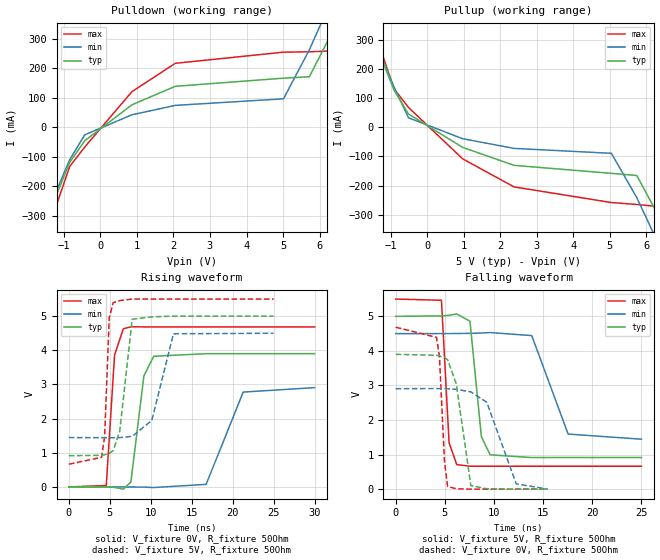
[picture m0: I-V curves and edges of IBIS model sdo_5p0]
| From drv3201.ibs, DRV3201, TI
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|   sdo_5p0 Model
[Model]   sdo_5p0
Model_type   Output
Polarity   Non-Inverting
Vmeas = 2.5
Vref = 0
Cref = 2pF
Rref = 300
|   typ   min   max
|   (nom PVT)   (fast PVT)   (slow PVT)
 C_comp   4.156e-12   3.993e-12   4.711e-12
| Where nom  PVT is Nominal Process, 5V, 27C
|   Fast PVT is Strong Process,  5.5V, -40C
|   Slow PVT is Weak Process,   4.5V, 150C
[Voltage Range]   5   4.5   5.5
|Junction Temperature
[Temperature Range]   27   150   -40
[Pullup Reference]   5   4.5   5.5
[Pulldown Reference]   0   0   0
[Power Clamp Reference]   5   4.5   5.5
[GND Clamp Reference]   0   0   0
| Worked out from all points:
|   slope of the pulldown table from 0 to 0.75 V, typ, clamps not added: 11.1 ohm
|   slope of the pullup table from 0 to 0.75 V, typ, clamps not added: 13.6 ohm
|   falling waveform, V_fixture 5V, R_fixture 50Ohm: 20-80 % time 741ps typ, 1.58ns min, 373ps max; typ from 5 V to 0.914 V
|   rising waveform, V_fixture 0V, R_fixture 50Ohm: 20-80 % time 1.01ns typ, 1.91ns min, 614ps max; typ from 0 V to 3.9 V
|   rising waveform, V_fixture 5V, R_fixture 50Ohm: 20-80 % time 733ps typ, 1.45ns min, 437ps max; typ from 0.914 V to 5 V
|   falling waveform, V_fixture 0V, R_fixture 50Ohm: 20-80 % time 983ps typ, 1.91ns min, 469ps max; typ from 3.9 V to 0 V
[Pulldown]
|   Voltage   I(typ)   I(min)   I(max)
-5V       -1.564A    -1.414A    -1.724A
-2.844V   -801.8mA   -722.4mA   -898.6mA
-1.375V   -282.9mA   -267.1mA   -326.5mA
-841.5mV  -119.7mA   -110.7mA   -134mA
-427.5mV  -46.2mA    -26.11mA   -67.41mA
863.5mV   75.69mA    41.89mA    120.2mA
2.051V    138.4mA    73.7mA     216.3mA
5.013V    166mA      96.02mA    254.1mA
5.72V     170.9mA    262.1mA    255.3mA
6.303V    311.4mA    424.2mA    258.4mA
6.891V    480.3mA    590.7mA    403.2mA
10V       1.469A     1.521A     1.429A
[Pullup]
|   Voltage   I(typ)   I(min)   I(max)
-5V       1.553A     1.452A     1.681A
-2.795V   773.3mA    730mA      842.4mA
-1.375V   273.1mA    276.8mA    302.4mA
-907.5mV  126.7mA    137.1mA    130.7mA
-513mV    45.04mA    32.06mA    67.37mA
968mV     -69.24mA   -39.56mA   -108.5mA
2.376V    -130.8mA   -72.78mA   -204.6mA
5.04V     -158.2mA   -89.55mA   -258.2mA
5.735V    -165.5mA   -241.2mA   -264.8mA
6.303V    -297.3mA   -392.6mA   -271.6mA
6.835V    -448.1mA   -537.1mA   -399.7mA
10V       -1.469A    -1.482A    -1.471A
[Ramp]
R_load = 50
|   typ   min   max
dV/dt_r   2.34058/1.00699e-09   1.74409/1.90147e-09   2.81133/6.09891e-10
dV/dt_f   2.45167/7.40092e-10   1.83304/1.56497e-09   2.90159/3.70435e-10
[Falling Waveform]
V_fixture = 5V
V_fixture_min = 4.5V
V_fixture_max = 5.5V
R_fixture = 50Ohm
|   Time   V(typ)   V(min)   V(max)
0s        5V         4.5V       5.5V
4.655ns   5.013V     4.501V     5.465V
5.432ns   5.032V     4.502V     1.339V
6.212ns   5.068V     4.503V     710.6mV
7.556ns   4.858V     4.508V     662.5mV
8.714ns   1.522V     4.517V     664mV
9.608ns   993.3mV    4.531V     664mV
13.84ns   914mV      4.443V     664mV
17.54ns   913.9mV    1.594V     664mV
25ns      913.9mV    1.445V     664mV
[Rising Waveform]
V_fixture = 0V
V_fixture_min = 0V
V_fixture_max = 0V
R_fixture = 50Ohm
|   Time   V(typ)   V(min)   V(max)
0s        2.412nV    151.2nV    5.105nV
4.571ns   -4.675mV   40.19uV    39.77mV
5.585ns   -15.52mV   -86.88uV   3.865V
6.653ns   -66.66mV   -764uV     4.631V
7.577ns   143.2mV    -2.086mV   4.688V
9.161ns   3.246V     -6.661mV   4.686V
10.36ns   3.826V     -18.85mV   4.685V
16.76ns   3.901V     74.03mV    4.686V
21.29ns   3.901V     2.777V     4.686V
30ns      3.901V     2.907V     4.686V
[Rising Waveform]
V_fixture = 5V
V_fixture_min = 4.5V
V_fixture_max = 5.5V
R_fixture = 50Ohm
|   Time   V(typ)   V(min)   V(max)
0s        913.9mV    1.445V     664mV
3.995ns   924.3mV    1.441V     866.5mV
4.37ns    939.5mV    1.44V      1.46V
4.934ns   983mV      1.44V      4.95V
5.417ns   1.063V     1.44V      5.397V
6.218ns   1.641V     1.443V     5.457V
7.736ns   4.911V     1.481V     5.501V
10.13ns   4.981V     1.945V     5.5V
12.77ns   5.001V     4.484V     5.5V
25ns      5V         4.5V       5.5V
[Falling Waveform]
V_fixture = 0V
V_fixture_min = 0V
V_fixture_max = 0V
R_fixture = 50Ohm
|   Time   V(typ)   V(min)   V(max)
0s        3.901V     2.907V     4.686V
4.145ns   3.873V     2.911V     4.392V
4.445ns   3.856V     2.91V      3.861V
4.967ns   3.804V     2.908V     794.1mV
5.282ns   3.746V     2.905V     79.44mV
6.167ns   3.042V     2.889V     9.179mV
7.646ns   101.9mV    2.814V     -484.6uV
9.266ns   12.77mV    2.513V     15.14uV
12.26ns   -58.73uV   152.9mV    -438.6nV
15.46ns   -58.51nV   1.817mV    -82.12nV
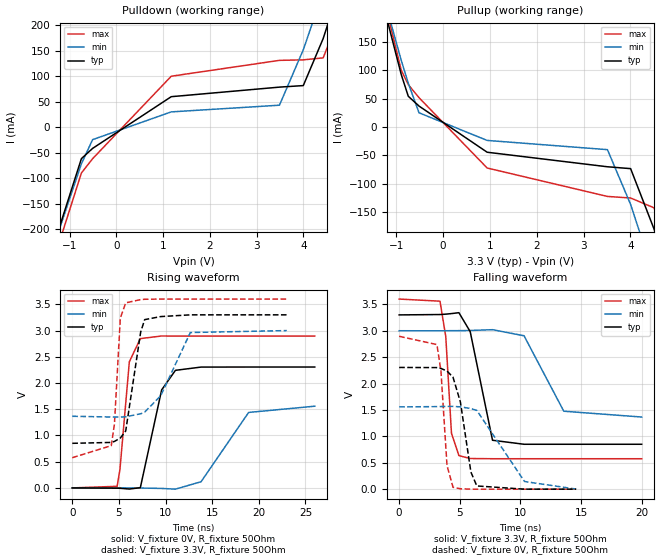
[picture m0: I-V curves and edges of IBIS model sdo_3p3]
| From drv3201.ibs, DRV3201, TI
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|   sdo_3p3 Model
[Model]   sdo_3p3
Model_type   Output
Polarity   Non-Inverting
Vmeas = 1.65
Vref = 0
Cref = 2pF
Rref = 300
|   typ   min   max
|   (nom PVT)   (fast PVT)   (slow PVT)
C_comp   3.809e-12   3.809e-12   4.123e-12
| Where nom  PVT is Nominal Process, 3.3V, 27C
|   Fast PVT is Strong Process,  3.6V, -40C
|   Slow PVT is Weak Process,   3V, 150C
[Voltage Range]   3.3   3   3.6
|Junction Temperature
[Temperature Range]   27   150   -40
[Pullup Reference]   3.3   3   3.6
[Pulldown Reference]   0   0   0
[Power Clamp Reference]   3.3   3   3.6
[GND Clamp Reference]   0   0   0
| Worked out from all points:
|   slope of the pulldown table from 0 to 0.495 V, typ, clamps not added: 15.5 ohm
|   slope of the pullup table from 0 to 0.495 V, typ, clamps not added: 18.8 ohm
|   falling waveform, V_fixture 3.3V, R_fixture 50Ohm: 20-80 % time 771ps typ, 1.71ns min, 459ps max; typ from 3.3 V to 0.85 V
|   rising waveform, V_fixture 0V, R_fixture 50Ohm: 20-80 % time 1.5ns typ, 2.96ns min, 827ps max; typ from 0 V to 2.31 V
|   rising waveform, V_fixture 3.3V, R_fixture 50Ohm: 20-80 % time 1.05ns typ, 2.25ns min, 558ps max; typ from 0.85 V to 3.3 V
|   falling waveform, V_fixture 0V, R_fixture 50Ohm: 20-80 % time 942ps typ, 2.22ns min, 470ps max; typ from 2.31 V to 0 V
[Pulldown]
|   Voltage   I(typ)   I(min)   I(max)
-3.3V     -890.9mA   -821.6mA   -986.4mA
-1.458V   -274.2mA   -268.7mA   -310mA
-1.238V   -202.6mA   -205.8mA   -231.5mA
-745.8mV  -61.74mA   -71.93mA   -89.89mA
-507mV    -41.71mA   -24.53mA   -61.92mA
1.174V    59.69mA    29.88mA    99.8mA
3.486V    78.44mA    43.02mA    130.9mA
3.996V    81.47mA    151.6mA    131.9mA
4.421V    173.7mA    265.3mA    135.8mA
4.795V    279.6mA    371.5mA    223.1mA
5.303V    425.2mA    516.9mA    372.4mA
6.6V      822.4mA    888.5mA    785.1mA
[Pullup]
|   Voltage   I(typ)   I(min)   I(max)
-3.3V     887.3mA    853.6mA    954.6mA
-1.39V    251.2mA    264.8mA    268.2mA
-896.4mV  92.89mA    117.9mA    100.5mA
-745.8mV  54.5mA     77.5mA     75.07mA
-516mV    37.19mA    25.33mA    51.94mA
939.6mV   -44.29mA   -23.44mA   -72.13mA
3.51V     -69.95mA   -39.73mA   -122.3mA
4.006V    -73.26mA   -136.5mA   -125.1mA
4.507V    -180mA     -263.2mA   -142.4mA
4.813V    -267.2mA   -345.9mA   -221.1mA
5.205V    -378.9mA   -451.8mA   -338.5mA
6.6V      -809.2mA   -849.2mA   -796.9mA
[Ramp]
R_load = 50
|   typ   min   max
dV/dt_r   1.38285/1.48814e-09   0.934919/2.95257e-09   1.73702/8.25926e-10
dV/dt_f   1.46991/7.65535e-10   0.980665/1.68403e-09   1.81426/4.5495e-10
[Falling Waveform]
V_fixture = 3.3V
V_fixture_min = 3V
V_fixture_max = 3.6V
R_fixture = 50Ohm
|   Time   V(typ)   V(min)   V(max)
0s        3.3V       3V         3.6V
3.368ns   3.307V     2.999V     3.56V
3.845ns   3.314V     3V         2.89V
4.316ns   3.325V     3.001V     1.058V
4.928ns   3.342V     3.002V     635.5mV
5.861ns   2.983V     3.005V     580.4mV
7.7ns     926.3mV    3.02V      576.3mV
10.3ns    850.2mV    2.905V     576.2mV
13.58ns   850.2mV    1.476V     576.2mV
20ns      850.1mV    1.366V     576.2mV
[Rising Waveform]
V_fixture = 0V
V_fixture_min = 0V
V_fixture_max = 0V
R_fixture = 50Ohm
|   Time   V(typ)   V(min)   V(max)
0s        2.322nV    191.7nV    3.793nV
4.811ns   -5.315mV   9.824uV    30.46mV
5.111ns   -7.036mV   -123uV     351.7mV
6.119ns   -21.58mV   -898.1uV   2.405V
7.298ns   4.196mV    -2.472mV   2.847V
9.581ns   1.868V     -10.01mV   2.897V
11.06ns   2.242V     -24.03mV   2.895V
13.81ns   2.304V     117.9mV    2.895V
18.91ns   2.305V     1.439V     2.895V
26ns      2.305V     1.558V     2.895V
[Rising Waveform]
V_fixture = 3.3V
V_fixture_min = 3V
V_fixture_max = 3.6V
R_fixture = 50Ohm
|   Time   V(typ)   V(min)   V(max)
0s        850.1mV    1.366V     576.2mV
4.181ns   867.3mV    1.352V     805.6mV
4.52ns    886.1mV    1.351V     1.216V
5.153ns   951mV      1.351V     3.238V
5.732ns   1.087V     1.356V     3.529V
7.337ns   2.975V     1.414V     3.591V
7.763ns   3.209V     1.446V     3.597V
9.479ns   3.267V     1.756V     3.601V
12.66ns   3.3V       2.963V     3.6V
23ns      3.3V       3V         3.6V
[Falling Waveform]
V_fixture = 0V
V_fixture_min = 0V
V_fixture_max = 0V
R_fixture = 50Ohm
|   Time   V(typ)   V(min)   V(max)
0s        2.305V     1.558V     2.895V
3.116ns   2.302V     1.563V     2.738V
3.446ns   2.286V     1.565V     2.244V
3.947ns   2.237V     1.567V     448.3mV
4.442ns   2.121V     1.567V     36.56mV
5.051ns   1.651V     1.559V     7.455mV
5.918ns   324.5mV    1.527V     374.7uV
6.407ns   60.82mV    1.49V      77.53uV
10.34ns   -48.52uV   145.1mV    -628.1nV
14.6ns    -90.58nV   1.355mV    -9.842nV
